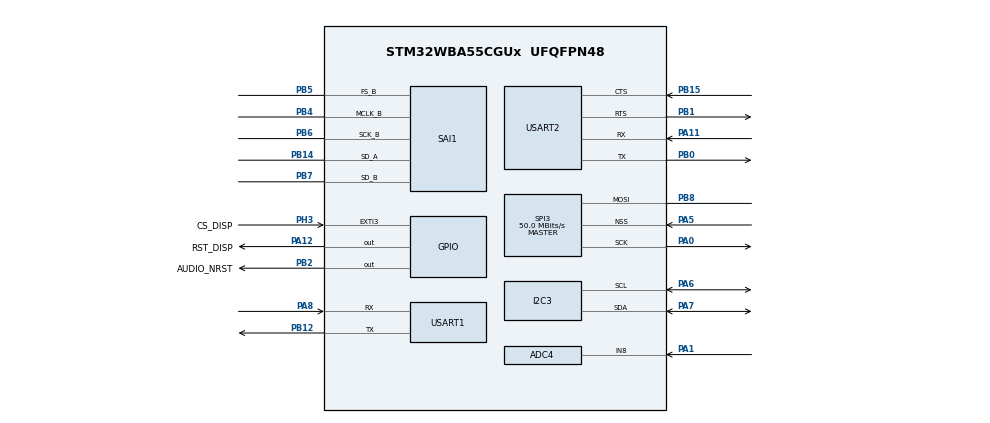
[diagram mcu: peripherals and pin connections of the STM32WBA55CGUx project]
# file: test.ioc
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ADC4.Channel-1\#ChannelRegularConversion=ADC_CHANNEL_8
ADC4.NbrOfConversionFlag=1
ADC4.Rank-1\#ChannelRegularConversion=1
ADC4.SamplingTime-1\#ChannelRegularConversion=ADC_SAMPLINGTIME_COMMON_1
ADC4.SelectedChannel=ADC_CHANNEL_8
CORTEX_M33_NS.userName=CORTEX_M33
I2C3.Timing=0x10C0ECFF
Mcu.Family=STM32WBA
Mcu.Name=STM32WBA55CGUx
Mcu.Package=UFQFPN48
NVIC.PriorityGroup=NVIC_PRIORITYGROUP_4
OSC_IN.Mode=HSE-External-Oscillator
OSC_IN.Signal=RCC_OSC_IN
OSC_OUT.Mode=HSE-External-Oscillator
OSC_OUT.Signal=RCC_OSC_OUT
PA0.Mode=Simplex_Bidirectional_Master
PA0.Signal=SPI3_SCK
PA1.Mode=IN8
PA1.Signal=ADC4_IN8
PA11.Mode=Asynchronous
PA11.Signal=USART2_RX
PA12.GPIO_Label=RST_DISP
PA12.Signal=GPIO_Output
PA13\ (JTMS/SWDIO).Mode=Serial_Wire
PA13\ (JTMS/SWDIO).Signal=DEBUG_JTMS-SWDIO
PA14\ (JTCK/SWCLK).Mode=Serial_Wire
PA14\ (JTCK/SWCLK).Signal=DEBUG_JTCK-SWCLK
PA5.Mode=NSS_Signal_Hard_Input
PA5.Signal=SPI3_NSS
PA6.Mode=I2C
PA6.Signal=I2C3_SCL
PA7.Mode=I2C
PA7.Signal=I2C3_SDA
PA8.Mode=Asynchronous
PA8.Signal=USART1_RX
PB0.Mode=Asynchronous
PB0.Signal=USART2_TX
PB1.Mode=CTS_RTS
PB1.Signal=USART2_RTS
PB12.Mode=Asynchronous
PB12.Signal=USART1_TX
PB14.Mode=SAI_A_SyncSlave
PB14.Signal=SAI1_SD_A
PB15.Mode=CTS_RTS
PB15.Signal=USART2_CTS
PB2.GPIO_Label=AUDIO_NRST
PB2.Signal=GPIO_Output
PB4\ (NJTRST).Mode=SAI_B_MasterWithClock
PB4\ (NJTRST).Signal=SAI1_MCLK_B
PB5.Mode=SAI_B_MasterWithClock
PB5.Signal=SAI1_FS_B
PB6.Mode=SAI_B_MasterWithClock
PB6.Signal=SAI1_SCK_B
PB7.Mode=SAI_B_MasterWithClock
PB7.Signal=SAI1_SD_B
PB8.Mode=Simplex_Bidirectional_Master
PB8.Signal=SPI3_MOSI
PC14-OSC32_IN.Mode=LSE-External-Oscillator
PC14-OSC32_IN.Signal=RCC_OSC32_IN
PC15-OSC32_OUT.Mode=LSE-External-Oscillator
PC15-OSC32_OUT.Signal=RCC_OSC32_OUT
PH3-BOOT0.GPIO_Label=CS_DISP
PH3-BOOT0.Signal=GPXTI3
ProjectManager.HeapSize=0x200
ProjectManager.StackSize=0x400
ProjectManager.TargetToolchain=STM32CubeIDE
RCC.ADCFreq_Value=100000000
RCC.AHB5CLKDivider=DIV4
RCC.AHBFreq_Value=100000000
RCC.APB1Freq_Value=100000000
RCC.APB1TimFreq_Value=100000000
RCC.APB2Freq_Value=100000000
RCC.APB2TimFreq_Value=100000000
RCC.CortexFreq_Value=12500000
RCC.HCLKFreq_Value=100000000
RCC.HSE_VALUE=32000000
RCC.HSI_VALUE=16000000
RCC.LSI1_VALUE=32000
RCC.LSI2_VALUE=32000
RCC.PLLFRACN=4096
RCC.PLLM=2
RCC.PLLN=12
RCC.PLLSourceVirtual=RCC_PLLSOURCE_HSE
RCC.PWR_Regulator_Voltage_Scale=PWR_REGULATOR_VOLTAGE_SCALE1
RCC.RTCClockSelection=RCC_RTCCLKSOURCE_LSE
RCC.SAI1CLockSelectionVirtual=RCC_SAI1CLKSOURCE_PLL1P
RCC.SYSCLKFreq_VALUE=100000000
RCC.SYSCLKSourceVirtual=RCC_SYSCLKSOURCE_PLLCLK
RCC.VCOOutputFreq_Value=200000000
SAI1.ErrorAudioFreq-SAI_B_MasterWithClock=1.72 %
SAI1.Instance-SAI_A_SyncSlave=SAI$Index_Block_A
SAI1.Instance-SAI_B_MasterWithClock=SAI$Index_Block_B
SAI1.MckOutput-SAI_B_MasterWithClock=SAI_MCK_OUTPUT_ENABLE
SAI1.RealAudioFreq-SAI_B_MasterWithClock=195.312 KHz
SAI1.VirtualMode-SAI_A_SyncSlave=VM_SLAVE
SAI1.VirtualMode-SAI_B_MasterWithClock=VM_MASTER
SPI3.CalculateBaudRate=50.0 MBits/s
SPI3.Direction=SPI_DIRECTION_1LINE
SPI3.Mode=SPI_MODE_MASTER
SPI3.VirtualNSS=VM_NSSHARD
SPI3.VirtualType=VM_MASTER
USART1.VirtualMode-Asynchronous=VM_ASYNC
USART2.VirtualMode-Asynchronous=VM_ASYNC
VP_CORTEX_M33_NS_VS_Hclk.Mode=Hclk_Mode
VP_ICACHE_VS_ICACHE.Mode=DirectMappedCache
VP_MEMORYMAP_VS_MEMORYMAP.Mode=CurAppReg
VP_PWR_VS_SECSignals.Mode=Security/Privilege
VP_RTC_VS_RTC_Activate.Mode=RTC_Enabled
board=STM32WBA55G-DK1

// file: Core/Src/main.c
/* USER CODE BEGIN Header */
/**
  ******************************************************************************
  * @file           : main.c
  * @brief          : Main program body
  ******************************************************************************
  * @attention
  *
  * Copyright (c) 2025 STMicroelectronics.
  * All rights reserved.
  *
  * This software is licensed under terms that can be found in the LICENSE file
  * in the root directory of this software component.
  * If no LICENSE file comes with this software, it is provided AS-IS.
  *
  ******************************************************************************
  */
/* USER CODE END Header */
#include "main.h"

ADC_HandleTypeDef hadc4;

I2C_HandleTypeDef hi2c3;

RTC_HandleTypeDef hrtc;

SAI_HandleTypeDef hsai_BlockA1;
SAI_HandleTypeDef hsai_BlockB1;

SPI_HandleTypeDef hspi3;

UART_HandleTypeDef huart1;
UART_HandleTypeDef huart2;

void SystemClock_Config(void);
static void MX_GPIO_Init(void);
static void MX_ADC4_Init(void);
static void MX_I2C3_Init(void);
static void MX_ICACHE_Init(void);
static void MX_RTC_Init(void);
static void MX_SAI1_Init(void);
static void MX_SPI3_Init(void);
static void MX_USART1_UART_Init(void);
static void MX_USART2_UART_Init(void);

int main(void)
{

  /* MCU Configuration--------------------------------------------------------*/

  /* Reset of all peripherals, Initializes the Flash interface and the Systick. */
  HAL_Init();

  /* Configure the system clock */
  SystemClock_Config();

  /* Initialize all configured peripherals */
  MX_GPIO_Init();
  MX_ADC4_Init();
  MX_I2C3_Init();
  MX_ICACHE_Init();
  MX_RTC_Init();
  MX_SAI1_Init();
  MX_SPI3_Init();
  MX_USART1_UART_Init();
  MX_USART2_UART_Init();

  /* Infinite loop */
  while (1)
  {

  }
}

void SystemClock_Config(void)
{
  RCC_OscInitTypeDef RCC_OscInitStruct = {0};
  RCC_ClkInitTypeDef RCC_ClkInitStruct = {0};

  /** Supply configuration update enable
  */
  HAL_PWREx_ConfigSupply(PWR_LDO_SUPPLY);

  /** Configure the main internal regulator output voltage
  */
  if (HAL_PWREx_ControlVoltageScaling(PWR_REGULATOR_VOLTAGE_SCALE1) != HAL_OK)
  {
    Error_Handler();
  }

  /** Configure LSE Drive Capability
  */
  HAL_PWR_EnableBkUpAccess();
  __HAL_RCC_LSEDRIVE_CONFIG(RCC_LSEDRIVE_MEDIUMLOW);

  /** Initializes the CPU, AHB and APB busses clocks
  */
  RCC_OscInitStruct.OscillatorType = RCC_OSCILLATORTYPE_HSE|RCC_OSCILLATORTYPE_LSE;
  RCC_OscInitStruct.HSEState = RCC_HSE_ON;
  RCC_OscInitStruct.HSEDiv = RCC_HSE_DIV1;
  RCC_OscInitStruct.LSEState = RCC_LSE_ON;
  RCC_OscInitStruct.PLL1.PLLState = RCC_PLL_ON;
  RCC_OscInitStruct.PLL1.PLLSource = RCC_PLLSOURCE_HSE;
  RCC_OscInitStruct.PLL1.PLLM = 2;
  RCC_OscInitStruct.PLL1.PLLN = 12;
  RCC_OscInitStruct.PLL1.PLLP = 2;
  RCC_OscInitStruct.PLL1.PLLQ = 2;
  RCC_OscInitStruct.PLL1.PLLR = 2;
  RCC_OscInitStruct.PLL1.PLLFractional = 4096;
  if (HAL_RCC_OscConfig(&RCC_OscInitStruct) != HAL_OK)
  {
    Error_Handler();
  }

  /** Initializes the CPU, AHB and APB busses clocks
  */
  RCC_ClkInitStruct.ClockType = RCC_CLOCKTYPE_HCLK|RCC_CLOCKTYPE_SYSCLK
                              |RCC_CLOCKTYPE_PCLK1|RCC_CLOCKTYPE_PCLK2
                              |RCC_CLOCKTYPE_PCLK7|RCC_CLOCKTYPE_HCLK5;
  RCC_ClkInitStruct.SYSCLKSource = RCC_SYSCLKSOURCE_PLLCLK;
  RCC_ClkInitStruct.AHBCLKDivider = RCC_SYSCLK_DIV1;
  RCC_ClkInitStruct.APB1CLKDivider = RCC_HCLK_DIV1;
  RCC_ClkInitStruct.APB2CLKDivider = RCC_HCLK_DIV1;
  RCC_ClkInitStruct.APB7CLKDivider = RCC_HCLK_DIV1;
  RCC_ClkInitStruct.AHB5_PLL1_CLKDivider = RCC_SYSCLK_PLL1_DIV4;
  RCC_ClkInitStruct.AHB5_HSEHSI_CLKDivider = RCC_SYSCLK_HSEHSI_DIV1;

  if (HAL_RCC_ClockConfig(&RCC_ClkInitStruct, FLASH_LATENCY_3) != HAL_OK)
  {
    Error_Handler();
  }
}

static void MX_ADC4_Init(void)
{

  ADC_ChannelConfTypeDef sConfig = {0};

  /** Common config
  */
  hadc4.Instance = ADC4;
  hadc4.Init.ClockPrescaler = ADC_CLOCK_ASYNC_DIV1;
  hadc4.Init.Resolution = ADC_RESOLUTION_12B;
  hadc4.Init.DataAlign = ADC_DATAALIGN_RIGHT;
  hadc4.Init.ScanConvMode = ADC_SCAN_DISABLE;
  hadc4.Init.EOCSelection = ADC_EOC_SINGLE_CONV;
  hadc4.Init.LowPowerAutoPowerOff = DISABLE;
  hadc4.Init.LowPowerAutonomousDPD = ADC_LP_AUTONOMOUS_DPD_DISABLE;
  hadc4.Init.LowPowerAutoWait = DISABLE;
  hadc4.Init.ContinuousConvMode = DISABLE;
  hadc4.Init.NbrOfConversion = 1;
  hadc4.Init.ExternalTrigConv = ADC_SOFTWARE_START;
  hadc4.Init.ExternalTrigConvEdge = ADC_EXTERNALTRIGCONVEDGE_NONE;
  hadc4.Init.DMAContinuousRequests = DISABLE;
  hadc4.Init.TriggerFrequencyMode = ADC_TRIGGER_FREQ_LOW;
  hadc4.Init.Overrun = ADC_OVR_DATA_PRESERVED;
  hadc4.Init.SamplingTimeCommon1 = ADC_SAMPLETIME_1CYCLE_5;
  hadc4.Init.SamplingTimeCommon2 = ADC_SAMPLETIME_1CYCLE_5;
  hadc4.Init.OversamplingMode = DISABLE;
  if (HAL_ADC_Init(&hadc4) != HAL_OK)
  {
    Error_Handler();
  }

  /** Configure Regular Channel
  */
  sConfig.Channel = ADC_CHANNEL_8;
  sConfig.Rank = ADC_REGULAR_RANK_1;
  sConfig.SamplingTime = ADC_SAMPLINGTIME_COMMON_1;
  if (HAL_ADC_ConfigChannel(&hadc4, &sConfig) != HAL_OK)
  {
    Error_Handler();
  }

}

static void MX_I2C3_Init(void)
{

  hi2c3.Instance = I2C3;
  hi2c3.Init.Timing = 0x10C0ECFF;
  hi2c3.Init.OwnAddress1 = 0;
  hi2c3.Init.AddressingMode = I2C_ADDRESSINGMODE_7BIT;
  hi2c3.Init.DualAddressMode = I2C_DUALADDRESS_DISABLE;
  hi2c3.Init.OwnAddress2 = 0;
  hi2c3.Init.OwnAddress2Masks = I2C_OA2_NOMASK;
  hi2c3.Init.GeneralCallMode = I2C_GENERALCALL_DISABLE;
  hi2c3.Init.NoStretchMode = I2C_NOSTRETCH_DISABLE;
  if (HAL_I2C_Init(&hi2c3) != HAL_OK)
  {
    Error_Handler();
  }

  /** Configure Analogue filter
  */
  if (HAL_I2CEx_ConfigAnalogFilter(&hi2c3, I2C_ANALOGFILTER_ENABLE) != HAL_OK)
  {
    Error_Handler();
  }

  /** Configure Digital filter
  */
  if (HAL_I2CEx_ConfigDigitalFilter(&hi2c3, 0) != HAL_OK)
  {
    Error_Handler();
  }

}

static void MX_ICACHE_Init(void)
{

  /** Enable instruction cache in 1-way (direct mapped cache)
  */
  if (HAL_ICACHE_ConfigAssociativityMode(ICACHE_1WAY) != HAL_OK)
  {
    Error_Handler();
  }
  if (HAL_ICACHE_Enable() != HAL_OK)
  {
    Error_Handler();
  }

}

static void MX_RTC_Init(void)
{

  RTC_PrivilegeStateTypeDef privilegeState = {0};

  /** Initialize RTC Only
  */
  hrtc.Instance = RTC;
  hrtc.Init.HourFormat = RTC_HOURFORMAT_24;
  hrtc.Init.AsynchPrediv = 127;
  hrtc.Init.SynchPrediv = 255;
  hrtc.Init.OutPut = RTC_OUTPUT_DISABLE;
  hrtc.Init.OutPutRemap = RTC_OUTPUT_REMAP_NONE;
  hrtc.Init.OutPutPolarity = RTC_OUTPUT_POLARITY_HIGH;
  hrtc.Init.OutPutType = RTC_OUTPUT_TYPE_OPENDRAIN;
  hrtc.Init.OutPutPullUp = RTC_OUTPUT_PULLUP_NONE;
  hrtc.Init.BinMode = RTC_BINARY_NONE;
  if (HAL_RTC_Init(&hrtc) != HAL_OK)
  {
    Error_Handler();
  }
  privilegeState.rtcPrivilegeFull = RTC_PRIVILEGE_FULL_NO;
  privilegeState.backupRegisterPrivZone = RTC_PRIVILEGE_BKUP_ZONE_NONE;
  privilegeState.backupRegisterStartZone2 = RTC_BKP_DR0;
  privilegeState.backupRegisterStartZone3 = RTC_BKP_DR0;
  if (HAL_RTCEx_PrivilegeModeSet(&hrtc, &privilegeState) != HAL_OK)
  {
    Error_Handler();
  }

}

static void MX_SAI1_Init(void)
{

  hsai_BlockA1.Instance = SAI1_Block_A;
  hsai_BlockA1.Init.Protocol = SAI_FREE_PROTOCOL;
  hsai_BlockA1.Init.AudioMode = SAI_MODESLAVE_RX;
  hsai_BlockA1.Init.DataSize = SAI_DATASIZE_8;
  hsai_BlockA1.Init.FirstBit = SAI_FIRSTBIT_MSB;
  hsai_BlockA1.Init.ClockStrobing = SAI_CLOCKSTROBING_FALLINGEDGE;
  hsai_BlockA1.Init.Synchro = SAI_SYNCHRONOUS;
  hsai_BlockA1.Init.OutputDrive = SAI_OUTPUTDRIVE_DISABLE;
  hsai_BlockA1.Init.NoDivider = SAI_MASTERDIVIDER_ENABLE;
  hsai_BlockA1.Init.FIFOThreshold = SAI_FIFOTHRESHOLD_EMPTY;
  hsai_BlockA1.Init.SynchroExt = SAI_SYNCEXT_DISABLE;
  hsai_BlockA1.Init.MckOutput = SAI_MCK_OUTPUT_ENABLE;
  hsai_BlockA1.Init.MonoStereoMode = SAI_STEREOMODE;
  hsai_BlockA1.Init.CompandingMode = SAI_NOCOMPANDING;
  hsai_BlockA1.Init.TriState = SAI_OUTPUT_NOTRELEASED;
  hsai_BlockA1.Init.PdmInit.Activation = DISABLE;
  hsai_BlockA1.Init.PdmInit.MicPairsNbr = 1;
  hsai_BlockA1.Init.PdmInit.ClockEnable = SAI_PDM_CLOCK1_ENABLE;
  hsai_BlockA1.FrameInit.FrameLength = 8;
  hsai_BlockA1.FrameInit.ActiveFrameLength = 1;
  hsai_BlockA1.FrameInit.FSDefinition = SAI_FS_STARTFRAME;
  hsai_BlockA1.FrameInit.FSPolarity = SAI_FS_ACTIVE_LOW;
  hsai_BlockA1.FrameInit.FSOffset = SAI_FS_FIRSTBIT;
  hsai_BlockA1.SlotInit.FirstBitOffset = 0;
  hsai_BlockA1.SlotInit.SlotSize = SAI_SLOTSIZE_DATASIZE;
  hsai_BlockA1.SlotInit.SlotNumber = 1;
  hsai_BlockA1.SlotInit.SlotActive = 0x00000000;
  if (HAL_SAI_Init(&hsai_BlockA1) != HAL_OK)
  {
    Error_Handler();
  }
  hsai_BlockB1.Instance = SAI1_Block_B;
  hsai_BlockB1.Init.Protocol = SAI_FREE_PROTOCOL;
  hsai_BlockB1.Init.AudioMode = SAI_MODEMASTER_TX;
  hsai_BlockB1.Init.DataSize = SAI_DATASIZE_8;
  hsai_BlockB1.Init.FirstBit = SAI_FIRSTBIT_MSB;
  hsai_BlockB1.Init.ClockStrobing = SAI_CLOCKSTROBING_FALLINGEDGE;
  hsai_BlockB1.Init.Synchro = SAI_ASYNCHRONOUS;
  hsai_BlockB1.Init.OutputDrive = SAI_OUTPUTDRIVE_DISABLE;
  hsai_BlockB1.Init.NoDivider = SAI_MASTERDIVIDER_ENABLE;
  hsai_BlockB1.Init.FIFOThreshold = SAI_FIFOTHRESHOLD_EMPTY;
  hsai_BlockB1.Init.AudioFrequency = SAI_AUDIO_FREQUENCY_192K;
  hsai_BlockB1.Init.SynchroExt = SAI_SYNCEXT_DISABLE;
  hsai_BlockB1.Init.MckOutput = SAI_MCK_OUTPUT_ENABLE;
  hsai_BlockB1.Init.MonoStereoMode = SAI_STEREOMODE;
  hsai_BlockB1.Init.CompandingMode = SAI_NOCOMPANDING;
  hsai_BlockB1.Init.TriState = SAI_OUTPUT_NOTRELEASED;
  hsai_BlockB1.Init.PdmInit.Activation = DISABLE;
  hsai_BlockB1.Init.PdmInit.MicPairsNbr = 1;
  hsai_BlockB1.Init.PdmInit.ClockEnable = SAI_PDM_CLOCK1_ENABLE;
  hsai_BlockB1.FrameInit.FrameLength = 8;
  hsai_BlockB1.FrameInit.ActiveFrameLength = 1;
  hsai_BlockB1.FrameInit.FSDefinition = SAI_FS_STARTFRAME;
  hsai_BlockB1.FrameInit.FSPolarity = SAI_FS_ACTIVE_LOW;
  hsai_BlockB1.FrameInit.FSOffset = SAI_FS_FIRSTBIT;
  hsai_BlockB1.SlotInit.FirstBitOffset = 0;
  hsai_BlockB1.SlotInit.SlotSize = SAI_SLOTSIZE_DATASIZE;
  hsai_BlockB1.SlotInit.SlotNumber = 1;
  hsai_BlockB1.SlotInit.SlotActive = 0x00000000;
  if (HAL_SAI_Init(&hsai_BlockB1) != HAL_OK)
  {
    Error_Handler();
  }

}

static void MX_SPI3_Init(void)
{

  SPI_AutonomousModeConfTypeDef HAL_SPI_AutonomousMode_Cfg_Struct = {0};

  /* SPI3 parameter configuration*/
  hspi3.Instance = SPI3;
  hspi3.Init.Mode = SPI_MODE_MASTER;
  hspi3.Init.Direction = SPI_DIRECTION_1LINE;
  hspi3.Init.DataSize = SPI_DATASIZE_8BIT;
  hspi3.Init.CLKPolarity = SPI_POLARITY_LOW;
  hspi3.Init.CLKPhase = SPI_PHASE_1EDGE;
  hspi3.Init.NSS = SPI_NSS_HARD_INPUT;
  hspi3.Init.BaudRatePrescaler = SPI_BAUDRATEPRESCALER_2;
  hspi3.Init.FirstBit = SPI_FIRSTBIT_MSB;
  hspi3.Init.TIMode = SPI_TIMODE_DISABLE;
  hspi3.Init.CRCCalculation = SPI_CRCCALCULATION_DISABLE;
  hspi3.Init.CRCPolynomial = 0x7;
  hspi3.Init.NSSPMode = SPI_NSS_PULSE_ENABLE;
  hspi3.Init.NSSPolarity = SPI_NSS_POLARITY_LOW;
  hspi3.Init.FifoThreshold = SPI_FIFO_THRESHOLD_01DATA;
  hspi3.Init.MasterSSIdleness = SPI_MASTER_SS_IDLENESS_00CYCLE;
  hspi3.Init.MasterInterDataIdleness = SPI_MASTER_INTERDATA_IDLENESS_00CYCLE;
  hspi3.Init.MasterReceiverAutoSusp = SPI_MASTER_RX_AUTOSUSP_DISABLE;
  hspi3.Init.MasterKeepIOState = SPI_MASTER_KEEP_IO_STATE_DISABLE;
  hspi3.Init.IOSwap = SPI_IO_SWAP_DISABLE;
  hspi3.Init.ReadyMasterManagement = SPI_RDY_MASTER_MANAGEMENT_INTERNALLY;
  hspi3.Init.ReadyPolarity = SPI_RDY_POLARITY_HIGH;
  if (HAL_SPI_Init(&hspi3) != HAL_OK)
  {
    Error_Handler();
  }
  HAL_SPI_AutonomousMode_Cfg_Struct.TriggerState = SPI_AUTO_MODE_DISABLE;
  if (HAL_SPIEx_SetConfigAutonomousMode(&hspi3, &HAL_SPI_AutonomousMode_Cfg_Struct) != HAL_OK)
  {
    Error_Handler();
  }

}

static void MX_USART1_UART_Init(void)
{

  huart1.Instance = USART1;
  huart1.Init.BaudRate = 115200;
  huart1.Init.WordLength = UART_WORDLENGTH_8B;
  huart1.Init.StopBits = UART_STOPBITS_1;
  huart1.Init.Parity = UART_PARITY_NONE;
  huart1.Init.Mode = UART_MODE_TX_RX;
  huart1.Init.HwFlowCtl = UART_HWCONTROL_NONE;
  huart1.Init.OverSampling = UART_OVERSAMPLING_16;
  huart1.Init.OneBitSampling = UART_ONE_BIT_SAMPLE_DISABLE;
  huart1.Init.ClockPrescaler = UART_PRESCALER_DIV1;
  huart1.AdvancedInit.AdvFeatureInit = UART_ADVFEATURE_NO_INIT;
  if (HAL_UART_Init(&huart1) != HAL_OK)
  {
    Error_Handler();
  }
  if (HAL_UARTEx_SetTxFifoThreshold(&huart1, UART_TXFIFO_THRESHOLD_1_8) != HAL_OK)
  {
    Error_Handler();
  }
  if (HAL_UARTEx_SetRxFifoThreshold(&huart1, UART_RXFIFO_THRESHOLD_1_8) != HAL_OK)
  {
    Error_Handler();
  }
  if (HAL_UARTEx_DisableFifoMode(&huart1) != HAL_OK)
  {
    Error_Handler();
  }

}

static void MX_USART2_UART_Init(void)
{

  huart2.Instance = USART2;
  huart2.Init.BaudRate = 115200;
  huart2.Init.WordLength = UART_WORDLENGTH_8B;
  huart2.Init.StopBits = UART_STOPBITS_1;
  huart2.Init.Parity = UART_PARITY_NONE;
  huart2.Init.Mode = UART_MODE_TX_RX;
  huart2.Init.HwFlowCtl = UART_HWCONTROL_RTS_CTS;
  huart2.Init.OverSampling = UART_OVERSAMPLING_16;
  huart2.Init.OneBitSampling = UART_ONE_BIT_SAMPLE_DISABLE;
  huart2.Init.ClockPrescaler = UART_PRESCALER_DIV1;
  huart2.AdvancedInit.AdvFeatureInit = UART_ADVFEATURE_NO_INIT;
  if (HAL_UART_Init(&huart2) != HAL_OK)
  {
    Error_Handler();
  }
  if (HAL_UARTEx_SetTxFifoThreshold(&huart2, UART_TXFIFO_THRESHOLD_1_8) != HAL_OK)
  {
    Error_Handler();
  }
  if (HAL_UARTEx_SetRxFifoThreshold(&huart2, UART_RXFIFO_THRESHOLD_1_8) != HAL_OK)
  {
    Error_Handler();
  }
  if (HAL_UARTEx_DisableFifoMode(&huart2) != HAL_OK)
  {
    Error_Handler();
  }

}

static void MX_GPIO_Init(void)
{
  GPIO_InitTypeDef GPIO_InitStruct = {0};

  /* GPIO Ports Clock Enable */
  __HAL_RCC_GPIOB_CLK_ENABLE();
  __HAL_RCC_GPIOA_CLK_ENABLE();
  __HAL_RCC_GPIOC_CLK_ENABLE();
  __HAL_RCC_GPIOH_CLK_ENABLE();

  /*Configure GPIO pin Output Level */
  HAL_GPIO_WritePin(RST_DISP_GPIO_Port, RST_DISP_Pin, GPIO_PIN_RESET);

  /*Configure GPIO pin Output Level */
  HAL_GPIO_WritePin(AUDIO_NRST_GPIO_Port, AUDIO_NRST_Pin, GPIO_PIN_RESET);

  /*Configure GPIO pin : RST_DISP_Pin */
  GPIO_InitStruct.Pin = RST_DISP_Pin;
  GPIO_InitStruct.Mode = GPIO_MODE_OUTPUT_PP;
  GPIO_InitStruct.Pull = GPIO_NOPULL;
  GPIO_InitStruct.Speed = GPIO_SPEED_FREQ_LOW;
  HAL_GPIO_Init(RST_DISP_GPIO_Port, &GPIO_InitStruct);

  /*Configure GPIO pin : AUDIO_NRST_Pin */
  GPIO_InitStruct.Pin = AUDIO_NRST_Pin;
  GPIO_InitStruct.Mode = GPIO_MODE_OUTPUT_PP;
  GPIO_InitStruct.Pull = GPIO_NOPULL;
  GPIO_InitStruct.Speed = GPIO_SPEED_FREQ_LOW;
  HAL_GPIO_Init(AUDIO_NRST_GPIO_Port, &GPIO_InitStruct);

  /*Configure GPIO pin : CS_DISP_Pin */
  GPIO_InitStruct.Pin = CS_DISP_Pin;
  GPIO_InitStruct.Mode = GPIO_MODE_IT_RISING;
  GPIO_InitStruct.Pull = GPIO_NOPULL;
  HAL_GPIO_Init(CS_DISP_GPIO_Port, &GPIO_InitStruct);

}

void Error_Handler(void)
{
  __disable_irq();
  while (1)
  {
  }
}
